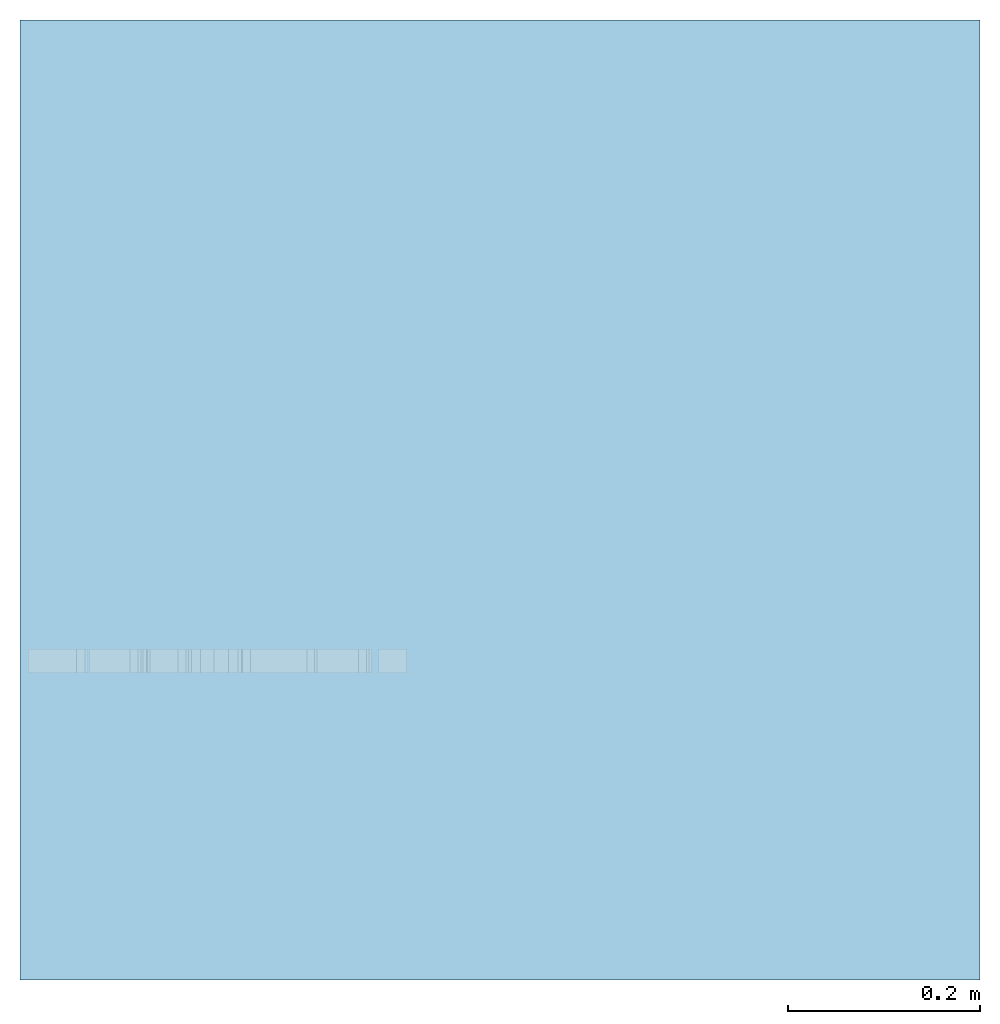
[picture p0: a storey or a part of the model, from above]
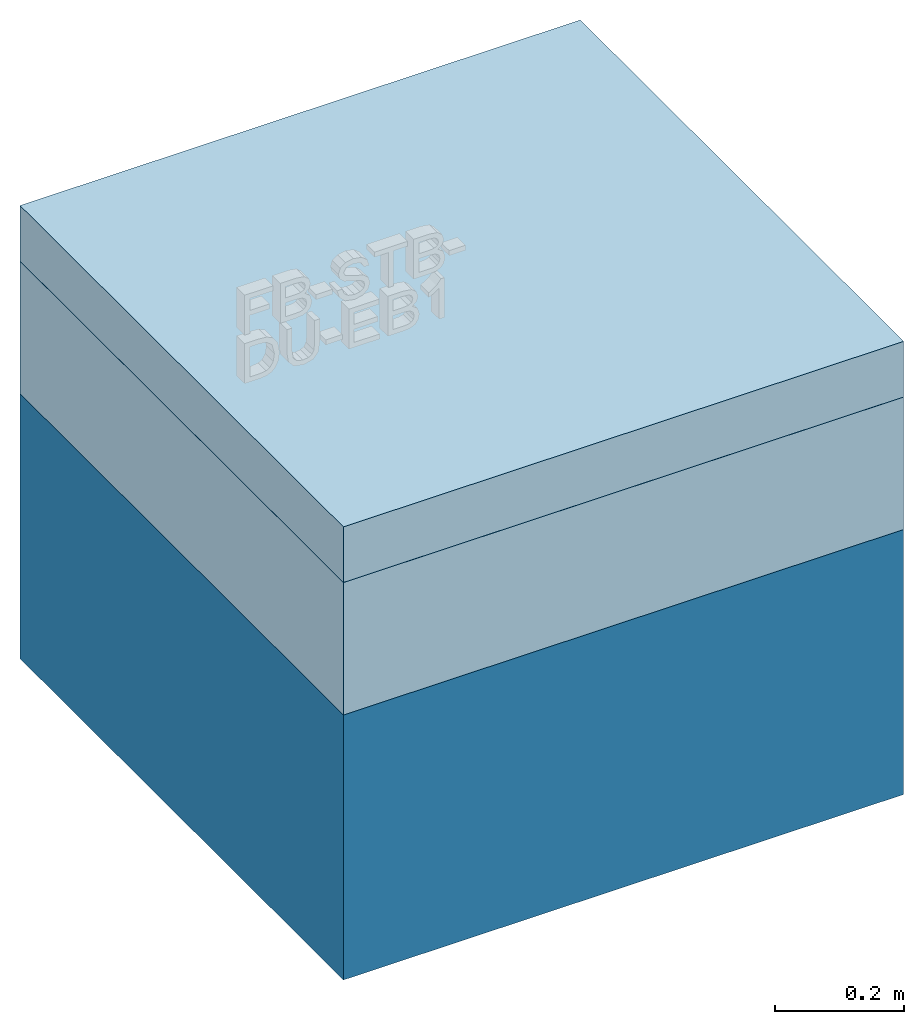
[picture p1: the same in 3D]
Properties of the parts of a building model (IFC4)

# File
Description: ViewDefinition [ReferenceView_V1.2], RevitIdentifiers [VersionGUID: 71a4b502-a2af-483b-88dc-542061cd4702, NumberOfSaves: 1], CoordinateReference [CoordinateBase: Gemeinsam genutzte Koordinaten], ExchangeRequirement [Architecture]
File name: 2018_01
Time: 2023-06-27T15:56:22+01:00
Written by: ODA SDAI 23.12
Made in: Autodesk Revit 24.0.5.432 (DEU) - IFC 24.0.5.432

# IfcProject, 2018_01
Phase: Projekt Status

# IfcSite, Default
RefLatitude: 48, 8, 15, 359802; RefLongitude: 11, 34, 47, 783432; RefElevation: 0 m
Pset_SiteCommon - Reference: Projektinformationen

# IfcBuildingElementProxy: Modelltext:075mm Arial, Modelltext:075mm Arial:2509569
In: Default
Type - Pset_BuildingElementProxyCommon - IsExternal: no
Pset_BuildingElementProxyCommon - Reference: 075mm Arial
Pset_EnvironmentalImpactIndicators - Reference: 075mm Arial
Qto_BuildingElementProxyQuantities - NetSurfaceArea: 0.139201 m2; NetVolume: 0.000463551 m3

# IfcElementAssembly: Geschossdecken Baugruppe:fbimSg_Footing_bc_WOD_vis_at_NTR_natuREbuilt_FB-STB-DU-EB1_GK3_86cm, Geschossdecken Baugruppe:fbimSg_Footing_bc_WOD_vis_at_NTR_natuREbuilt_FB-STB-DU-EB1_GK3_86cm:2509591
In: Default
PredefinedType: USERDEFINED; Material: fbim_18108010_AT_015_Parkettboden, fbim_16053507_AT_Trockenestrich_gips, fbim_14100505_AT_Schafwolle, fbim_14104055_AT_040_HF-Trittschalldaemmplatte
Pset_ElementAssemblyCommon - Reference: fbimSg_Footing_bc_WOD_vis_at_NTR_natuREbuilt_FB-STB-DU-EB1_GK3_86cm; sets with these values: 2

# IfcSlab: Geschossdecke:fbimSg_Floor_dp_INH_vis_at_NTR_natuREbuilt_FBuD_GK3_o_50cm, Geschossdecke:fbimSg_Floor_dp_INH_vis_at_NTR_natuREbuilt_FBuD_GK3_o_50cm:2509572
In: Default
Type - PredefinedType: FLOOR; Material: fbim_18108010_AT_015_Parkettboden, fbim_16053507_AT_Trockenestrich_gips, fbim_14100505_AT_Schafwolle, fbim_14104055_AT_040_HF-Trittschalldaemmplatte
Type - Pset_SlabCommon - IsExternal: no
Pset_EnvironmentalImpactIndicators - Reference: fbimSg_Floor_dp_INH_vis_at_NTR_natuREbuilt_FBuD_GK3_o_50cm; sets with these values: 2
Pset_SlabCommon - Reference: fbimSg_Floor_dp_INH_vis_at_NTR_natuREbuilt_FBuD_GK3_o_50cm; PitchAngle: 0 deg; LoadBearing: no
Qto_SlabBaseQuantities - fbim_18108010_AT_015_Parkettboden, Width: 0.015 m; fbim_16053507_AT_Trockenestrich_gips, Width: 0.02 m; fbim_14100505_AT_Schafwolle, Width: 0.05 m; fbim_14104055_AT_040_HF-Trittschalldaemmplatte, Width: 0.02 m; Width: 0.105 m; Length: 1 m; Depth: 0.02 m; Perimeter: 4 m; GrossArea: 1 m2; GrossVolume: 0.02 m3; NetVolume: 0.105 m3

# IfcSlab: Geschossdecke:fbimSg_Floor_dp_INS_vis_at_NTR_natuREbuilt_FBuD_GK3_u_10,5cm, Geschossdecke:fbimSg_Floor_dp_INS_vis_at_NTR_natuREbuilt_FBuD_GK3_u_10,5cm:2509586
In: Default
Type - PredefinedType: FLOOR; Material: fbim_14103005_AT_Schaumglasschotter
Type - Pset_SlabCommon - IsExternal: no
Pset_EnvironmentalImpactIndicators - Reference: fbimSg_Floor_dp_INS_vis_at_NTR_natuREbuilt_FBuD_GK3_u_10,5cm; sets with these values: 2
Pset_SlabCommon - PitchAngle: 0 deg; LoadBearing: no; Reference: fbimSg_Floor_dp_INS_vis_at_NTR_natuREbuilt_FBuD_GK3_u_10,5cm
Qto_SlabBaseQuantities - fbim_14103005_AT_Schaumglasschotter, Width: 0.5 m; Width: 0.5 m; Length: 1 m; Depth: 0.5 m; Perimeter: 4 m; GrossArea: 1 m2; GrossVolume: 0.5 m3; NetVolume: 0.5 m3

# IfcSlab: Geschossdecke:fbimSg_Slab_sb_CNR_vis_at_NTR_natuREbuilt_FBuD_GK3_k_25cm, Geschossdecke:fbimSg_Slab_sb_CNR_vis_at_NTR_natuREbuilt_FBuD_GK3_k_25cm:2509579
In: Default
Type - PredefinedType: FLOOR; Material: fbim_12050505_AT_025_Stahlbeton_C25_30_GK32
Type - Pset_SlabCommon - IsExternal: no
Pset_EnvironmentalImpactIndicators - Reference: fbimSg_Slab_sb_CNR_vis_at_NTR_natuREbuilt_FBuD_GK3_k_25cm; sets with these values: 2
Pset_SlabCommon - PitchAngle: 0 deg; LoadBearing: no; Reference: fbimSg_Slab_sb_CNR_vis_at_NTR_natuREbuilt_FBuD_GK3_k_25cm
Qto_SlabBaseQuantities - Width: 1 m; Length: 1 m; Depth: 0.25 m; Perimeter: 4 m; GrossArea: 1 m2; GrossVolume: 0.25 m3; NetVolume: 0.25 m3
